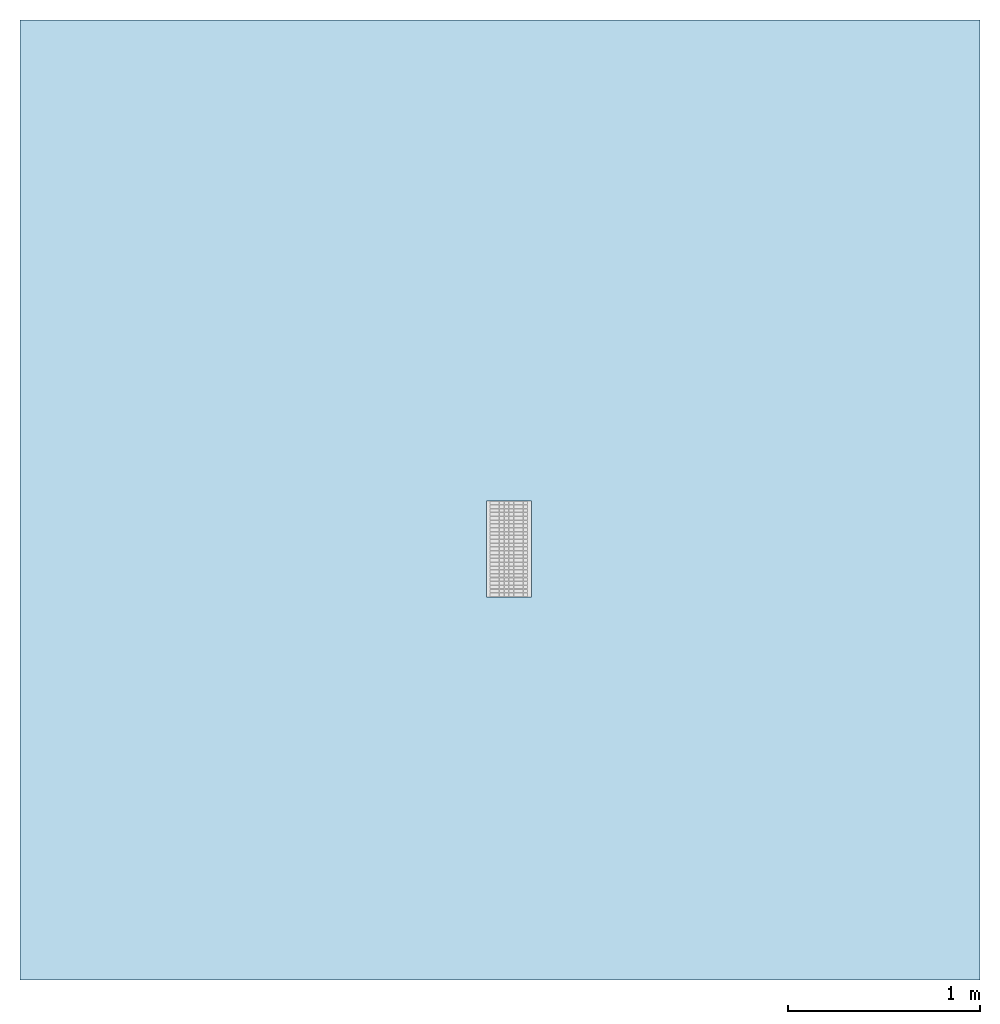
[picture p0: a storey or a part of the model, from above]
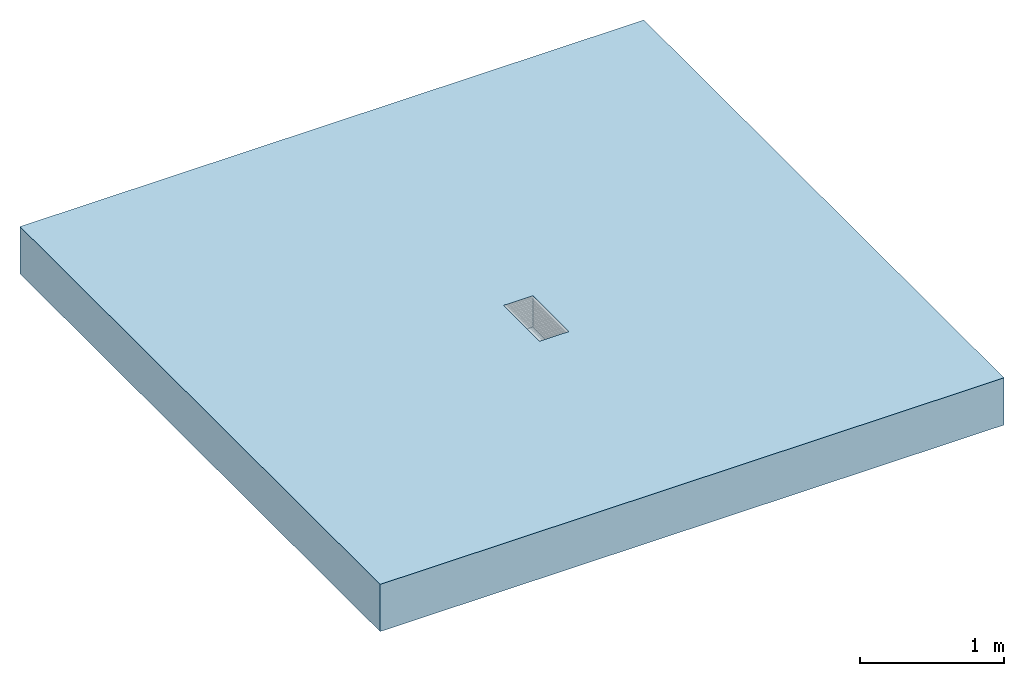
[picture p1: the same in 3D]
Properties of the parts of a building model (IFC2X3)

# File
Description: ViewDefinition [CoordinationView]
File name: 24213 - No 0.1J Constant Depth Channel - 500mm LG - Invert Depth 240mm.ifc
Time: 2013-10-16T12:49:31
Written by: Autodesk Revit 2013
Made in: 20120221_2030(x64)

# IfcProject, Project Number
LongName: Project Name; Phase: Project Status

# IfcSite, Default
RefLatitude: 42, 21, 30, 344238; RefLongitude: -71, -3, -35, -194702; RefElevation: 0 mm

# IfcBuilding
Pset_BuildingCommon - NumberOfStoreys: 1
Other - Client Name: Owner; Project Name: Project Name; Project Status: Project Status; Project Address: ## Street City, State Zip; Project Issue Date: Issue Date; Project Number: Project Number

# IfcBuildingStorey, Level 1
LongName: Level 1; Elevation: 0 mm
Constraints - Elevation Base: 0; Elevation: 0 mm
Graphics - Line Weight: 1; Color: 0; Symbol at End 2 Default: yes; Symbol at End 1 Default: no; Line Pattern: Center; Symbol: M_Level Head - Circle: M_Level Head - Circle
Identity Data - Structural: no; Building Story: yes; Name: Level 1
Dimensions - Computation Height: 0 mm

# IfcBuildingElementProxy: 24213 - No 0.1J Constant Depth Channel - 500mm LG - Invert Depth 240mm, Civil-Drainage-Channel-ACO-MultiDrain-M200DS-Channel-System:24213 - No 0.1J Constant Depth Channel - 500mm LG - Invert Depth 240mm:24213 - No 0.1J Constant Depth Channel - 500mm LG - Invert Depth 240mm:1152340
In: Level 1
Material: Vienite® Synthetic Resin Concrete
Dimensions - EndCap Position: 500 mm; FloorCut_Length: -500 mm; Volume: 8946111 mm3; Length: 1000 mm; Custom_Value_Length: 0 mm; EndCap_Height: 265 mm; FloorCut_Depth: 265 mm; FloorCut_Width: 235 mm; Depth: 265 mm; InvDepth: 140 mm; FloorCut_HorPosition: 117.5 mm
Constraints - Level: Level: Level 1; Moves With Nearby Elements: no
Construction - 23219 - Universal Endcap (Male End): no; 13449 - Grating - Mesh - Stainless Steel - 500mm Long: no; 13448 - Grating - Mesh - Stainless Steel - 1000mm Long: no; 23219 - Universal Endcap (Female End): no; Constant Depth Channel_1000: no; Constant Depth Channel_500: yes; Grating_1000mm: no; Grating_500mm: yes; 23410_Sump Unit: no; Shallow Depth Channel with seal: no; Shallow Depth Channel: no
Phasing - Phase Created: New Construction
Pset_BuildingElementProxyCommon - Reference: 24213 - No 0.1J Constant Depth Channel - 500mm LG - Invert Depth 240mm
General - SerialNumber: 0; TagNumber: 0
Green Building Properties - Channel Recyclable: Fully recyclable; Channel Recycled Material Content: 20% minimum; Edge Rail Recyclable: Fully recyclable; Edge Rail Recycled Material Content: Between 40% - 90%
Data - Load Class: A 15 - D 400; Product Standard: BS EN 1433:2002, CE marked; Invert Depth: 240mm; Concrete Surround Volume - Load Class A 15 - Concrete Pavement: 0.11m³/m; Concrete Surround Volume - Load Class B 125 - C 250 - Concrete Pavement: 0.17m³/m; Channel C.S.A: 0.035m²; Product Weight: 18.9 Kg; Product Dimensions: 500mm x 235mm x 265mm (LxWxH); Concrete Surround Volume - Load Class D 400 - Concrete Pavement: 0.24m³/m; Hydraulic Performance: http://www.aco.co.uk/download.php?id=173; Installation - Concrete Grade: Refer to brochure; ACO Hydraulic Design Software: http://www.acodesign.co.uk
Identity Data - Watermarked By: www.aco.co.uk; Assembly Code: D2040; e-mail Technical: technical@aco.co.uk; OmniClass Number: 23.70.50.24; Assembly Description: Rain Water Drainage; Model Description: Channel drainage system; Watermarked With: BIM Manager Premium Suite; OmniClass Title: Rainwater Removal; Address: ACO Business Park, Hitchin Road, Shefford, Bedfordshire, United Kingdom SG17 5TE; Product Page URL: http://www.aco.co.uk/product_detail.php?id=15; Product Code: 24213; e-mail Sales: customersupport@aco.co.uk; Cost: 0; Product brochure: http://www.aco.co.uk/download.php?id=173; Model: ACO MultiDrain MD - M200DS; Installation guidelines: http://www.aco.co.uk/download.php?id=173; Watermark 2: This file is water marked and users are prohibited to reproduce, adapt, distribute this information; Type Comments: ACO MultiDrain M200DS 0.1J Constant Depth Channel 500mm Long; Manufacturer: ACO Technologies plc - ACO Water Management Division; Maintenance guidelines: http://www.aco.co.uk/download.php?id=173; Fax: +44 (0)1462 815895; URL: www.aco.co.uk; Watermark 1: This file is the property of ACO Technologies PLC; Price: POA - contact ACO; Telephone: +44 (0)1462 816666
Model Properties - Grating Product code 13449: Load Class C250 - Mesh Stainless Steel Grade 304 13449DL 500mm long - 23x17mm slot - Intake area 154100mm²/m - 6.0kg; Grating Product code 13448: N/A; End Cap Product code 23219: No 306 Universal End Cap - 235mm wide x 365mm long - Spigot Ø160mm x 75mm long - Silver - Polypropylene - 0.4kg
Materials and Finishes - Edge Rail Material: Stainless Steel Grade 304; Channel Material: Vienite® Synthetic Resin Concrete; Edge Rail Colour: Self; Channel Colour: Brown
Other - Revision: 1; CreatedBy: www.aco.co.uk

# IfcOpeningElement: Recess
In: Level 1
Structural - Structural: no; Enable Analytical Model: no
Phasing - Phase Created: New Construction
Dimensions - Volume: 9968862500 mm3; Area: 25000000 mm2; Thickness: 400 mm; Perimeter: 20000 mm
Constraints - Level: Level: Level 1; Height Offset From Level: 0 mm; Related to Mass: no; Room Bounding: yes
Analytical Properties - Absorptance: 0.1; Heat Transfer Coefficient (U): 2.0925; Roughness: 1; Thermal mass: 543920; Thermal Resistance (R): 0.477897
Construction - Default Thickness: 400 mm; Function: 0
Graphics - Coarse Scale Fill Color: 0
Materials and Finishes - Structural Material: Earth

# IfcSlab: Floor:Generic Floor - 400mm, Floor:Generic Floor - 400mm:193825
In: Level 1
PredefinedType: FLOOR; Material: Earth 400 mm
Structural - Structural: no; Enable Analytical Model: no
Phasing - Phase Created: New Construction
Dimensions - Volume: 9968862500 mm3; Area: 25000000 mm2; Thickness: 400 mm; Perimeter: 20000 mm
Constraints - Level: Level: Level 1; Height Offset From Level: 0 mm; Related to Mass: no; Room Bounding: yes
Pset_SlabCommon - Reference: Generic Floor - 400mm; IsExternal: no; LoadBearing: yes
Analytical Properties - Absorptance: 0.1; Heat Transfer Coefficient (U): 2.0925; Roughness: 1; Thermal mass: 543920; Thermal Resistance (R): 0.477897
Construction - Default Thickness: 400 mm; Function: 0
Graphics - Coarse Scale Fill Color: 0
Materials and Finishes - Structural Material: Earth
